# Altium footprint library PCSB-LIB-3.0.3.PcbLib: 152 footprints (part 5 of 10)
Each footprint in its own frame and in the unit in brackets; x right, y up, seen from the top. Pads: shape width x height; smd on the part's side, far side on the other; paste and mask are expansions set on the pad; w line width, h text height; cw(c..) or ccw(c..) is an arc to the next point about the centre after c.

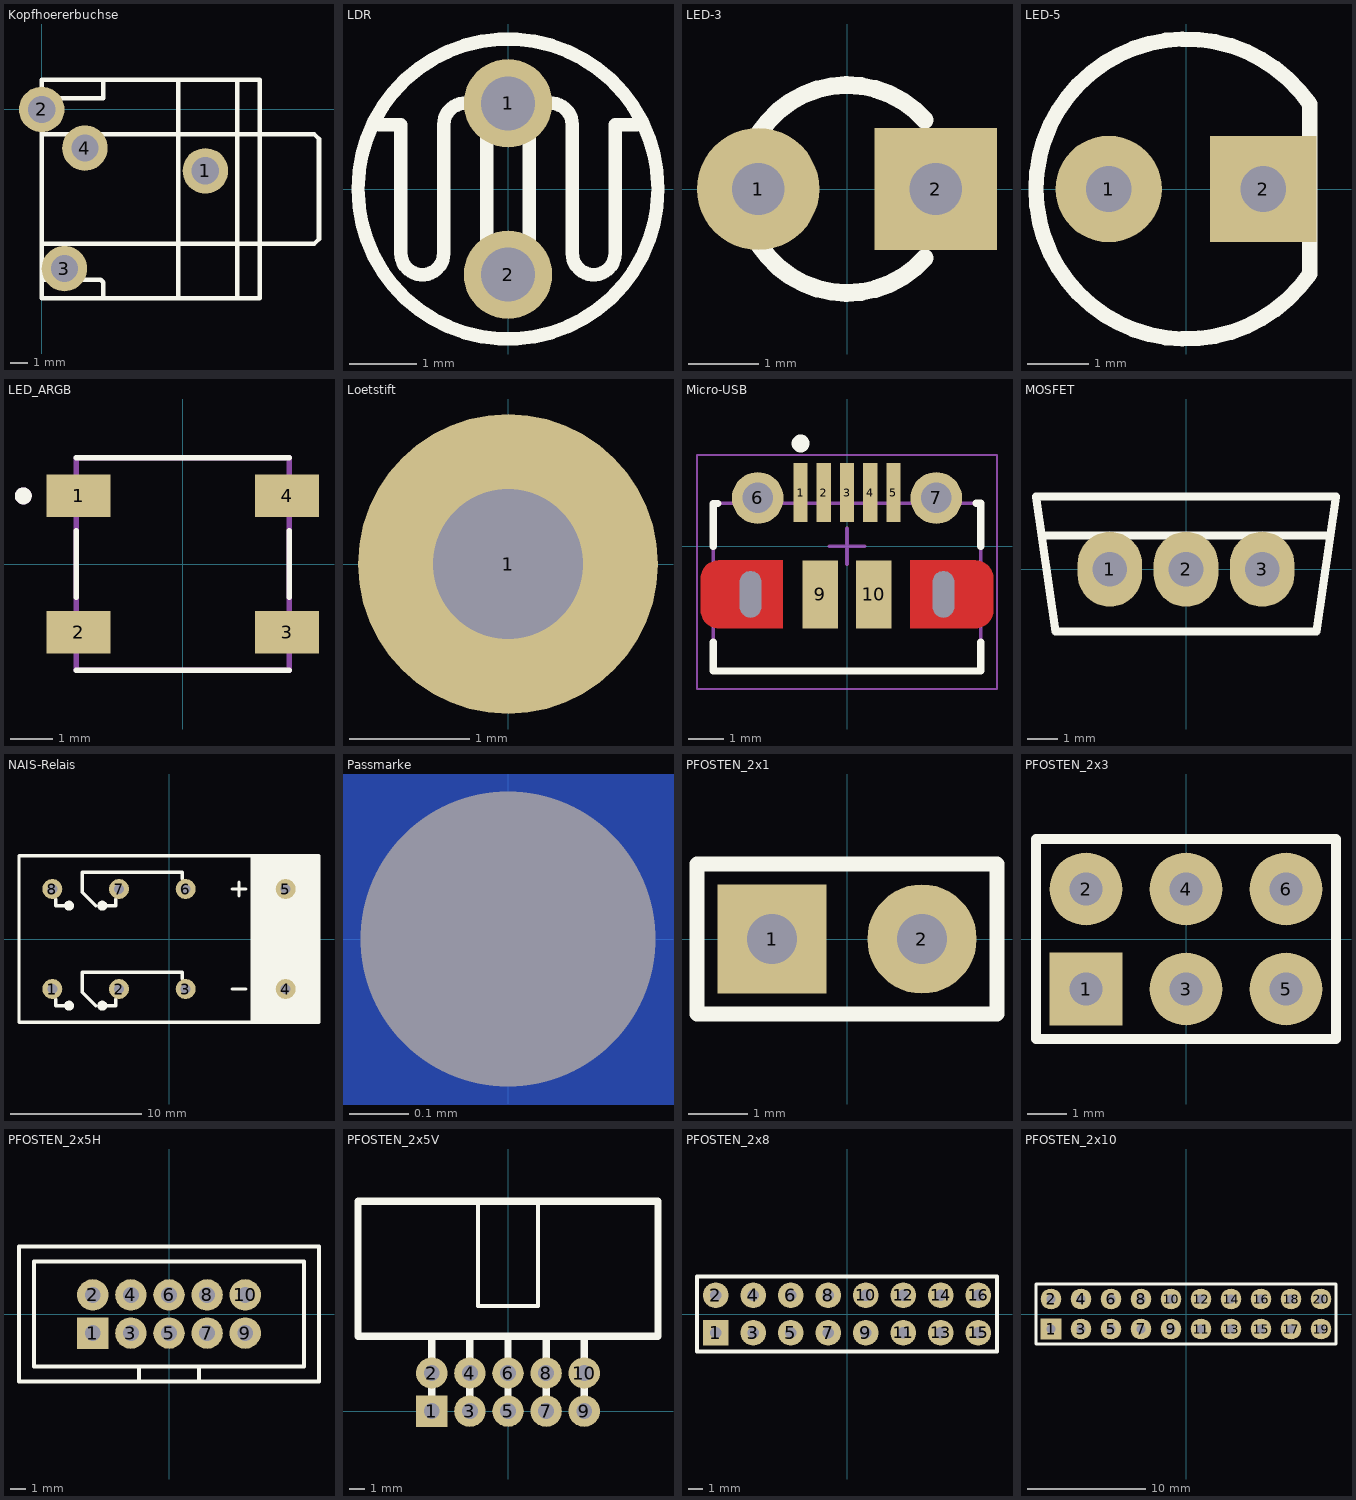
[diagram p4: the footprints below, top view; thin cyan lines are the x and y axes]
## Kopfhoererbuchse [mil]
pads (4):
  round 100 hole 60: 1(360,-135) 2(0,0) 3(50,-350) 4(95,-85)
Top Overlay:
  lines w10: 0,-375 130,-375 135,-380 135,-415 ; 0,-295 480,-295 600,-295 610,-285 610,-65 600,-55 480,-55 0,-55 ; 0,25 135,25 135,65 ; 300,-415 300,65 ; 430,-415 430,65 ; 0,-415 480,-415 480,65 0,65 0,-415

## LDR [mm]
pads (2):
  round 1.308 hole 0.8: 1(0,1.27) 2(0,-1.27)
Top Overlay:
  circle w0.2: c0,0 r2.222
  lines w0.2: -1.905,0.953 -1.587,0.953 -1.587,-0.953 ccw(c-1.27,-0.953) -0.953,-0.953 -0.953,0.953 cw(c-0.635,0.953) -0.318,0.953 -0.318,-0.953 ; 0.318,-0.953 0.318,0.953 cw(c0.635,0.953) 0.953,0.953 0.953,-0.953 ccw(c1.27,-0.953) 1.587,-0.953 1.587,0.953 1.905,0.953
Mechanical 13:
  lines w0.2: -0.318,-0.953 ccw(c0,-0.953) 0.318,-0.953

## LED-3 [mm]
pads (2):
  round 1.75 hole 0.75: 1(-1.27,0)
  rect 1.75x1.75 hole 0.75: 2(1.27,0)
Top Overlay:
  lines w0.254: 1.111,-0.988 cw(c0,0) 1.111,0.988 ; 1.397,-0.508 1.397,0.508

## LED-5 [mm]
pads (2):
  round 1.75 hole 0.75: 1(-1.27,0)
  rect 1.75x1.75 hole 0.75: 2(1.27,0)
Top Overlay:
  lines w0.254: 2.032,-1.397 cw(c0,0) 2.032,1.397 2.032,-1.397

## LED_ARGB [mm]
pads (4):
  rect 1.5x1 smd: 1(-2.45,1.6) 2(-2.45,-1.6) 3(2.45,-1.6) 4(2.45,1.6)
Top Overlay:
  circle w0.2: c-3.75,1.6 r0.1
  lines w0.127: -2.5,-2.5 2.5,-2.5 ; -2.5,-0.787 -2.5,0.787 ; -2.5,2.5 2.5,2.5 ; 2.5,-0.787 2.5,0.787
Mechanical 13:
  circle w0.2: c-3.75,1.6 r0.1
  lines w0.127: -2.5,-2.5 2.5,-2.5 2.5,2.5 -2.5,2.5 -2.5,-2.5

## Loetstift [mm]
pads (1):
  round 2.5 hole 1.25: 1(0,0)

## Micro-USB [mm] "USB, MICRO B, Body 7.491x4.695 mm, Pitch 0.65 mm"
height 2.673
pads (11):
  rect 0.4x1.65 smd: 1(-1.3,1.5) 2(-0.65,1.5) 3(0,1.5) 4(0.65,1.5) 5(1.3,1.5)
  round 1.45 hole 0.85: 6(-2.5,1.35) 7(2.5,1.35)
  rrect50% 0x0 hole 0.6 slot 1.3 at 90 deg: 8(-2.7,-1.35) 11(2.7,-1.35)
  rect 1x1.9 smd: 9(-0.75,-1.35) 10(0.75,-1.35)
Top Layer:
  circle w0.5: c3.6,-0.9 r0.25
  circle w0.5: c3.6,-1.8 r0.25
  circle w0.5: c-3.6,-0.9 r0.25
  circle w0.5: c-3.6,-1.8 r0.25
  region: 3.6,-0.9 3.6,-1.8 4.1,-1.8 4.1,-0.9
  region: 1.775,-0.4 1.775,-2.3 3.6,-2.3 3.6,-0.4
  region: -3.6,-1.8 -3.6,-0.9 -4.1,-0.9 -4.1,-1.8
  region: -1.8,-2.3 -1.8,-0.4 -3.6,-0.4 -3.6,-2.3
Top Overlay:
  circle w0.25: c-1.3,2.875 r0.125
  lines w0.2: -3.745,-2.688 -3.745,-3.5 3.745,-3.5 3.745,-2.688 ; -3.745,-0.012 -3.745,1.195 -3.614,1.195 ; 3.615,1.2 3.745,1.2 3.745,-0.012
Mechanical 13:
  lines w0.1: -3.75,1.2 3.745,1.2 3.745,-3.5 -3.745,-3.5 -3.745,1.195
Mechanical 15:
  lines w0.05: -4.2,-4 4.2,-4 4.2,2.55 -4.2,2.55 -4.2,-4
  lines w0.1: -0.5,0 0.5,0 ; 0,-0.5 0,0.5

## MOSFET [mm]
pads (3):
  oval 2.15x2.5 hole 1.15: 1(-2.54,0) 2(0,0) 3(2.54,0)
Top Overlay:
  lines w0.254: -4.812,1.125 4.808,1.125 ; -5,2.425 0,2.425 5,2.425 4.35,-2.075 0,-2.075 -4.35,-2.075 -5,2.425

## NAIS-Relais [mil]
pads (8):
  round 60 hole 30: 1(-350,-150) 2(-150,-150) 3(50,-150) 4(350,-150) 5(350,150) 6(50,150) 7(-150,150) 8(-350,150)
Top Overlay:
  circle w10: c-300,-200 r10
  circle w10: c-200,-200 r10
  circle w10: c-300,100 r10
  circle w10: c-200,100 r10
  rectangle: 250,-250 450,250
  region: -310,-190 -290,-190 -290,-210 -310,-210
  region: -210,-190 -190,-190 -190,-210 -210,-210
  region: -206,109 -192,109 -192,93 -194,91 -207,91 -207,108
  region: -306,109 -305,108 -293,108 -293,94 -295,92 -302,92 -302,103 -307,108
  region: -290,100 -300,100 -299,99 -299,90 -300,90 -302,92 -300,94 -300,102 -295,97 -295,92
  lines w10: -340,-180 -340,-200 -300,-200 ; -340,120 -340,100 -300,100 ; -220,-200 -260,-160 -260,-120 -260,-100 40,-100 40,-120 ; -220,100 -260,140 -260,180 -260,200 40,200 40,180 ; -200,-200 -160,-200 -160,-180 ; -200,100 -160,100 -160,120 ; 190,-150 230,-150 ; 190,150 230,150 ; 210,130 210,170 ; 250,-250 250,250 ; -450,-250 450,-250 450,250 -450,250 -450,-250

## Passmarke [mm]
pads (1):
  round 0 hole 0.5 unplated: 0(0,0)
Bottom Layer:
  circle w0.5: c0,0 r0.25

## PFOSTEN_2x1 [mm]
pads (2):
  rect 1.85x1.85 hole 0.85 mask+0.102: 1(-1.27,0)
  round 1.85 hole 0.85 mask+0.102: 2(1.27,0)
Top Overlay:
  lines w0.254: -2.54,-1.27 -2.54,1.27 2.54,1.27 2.54,-1.27 -2.54,-1.27

## PFOSTEN_2x3 [mm]
pads (6):
  rect 1.85x1.85 hole 0.85 mask+0.102: 1(-2.54,-1.27)
  round 1.85 hole 0.85 mask+0.102: 2(-2.54,1.27) 3(0,-1.27) 4(0,1.27) 5(2.54,-1.27) 6(2.54,1.27)
Top Overlay:
  lines w0.254: -3.81,-2.54 3.81,-2.54 3.81,2.54 -3.81,2.54 -3.81,-2.54

## PFOSTEN_2x5H [mm]
height 9
pads (10):
  rect 2.1x2.1 hole 1.05 mask+0.102: 1(-5.08,-1.27)
  round 2.1 hole 1.05 mask+0.102: 2(-5.08,1.27) 3(-2.54,-1.27) 4(-2.54,1.27) 5(0,-1.27) 6(0,1.27) 7(2.54,-1.27) 8(2.54,1.27) 9(5.08,-1.27) 10(5.08,1.27)
Top Overlay:
  lines w0.254: -2,-4.5 -2,-3.5 ; -0.5,4.5 10,4.5 10,-4.5 -10,-4.5 -10,4.5 0,4.5 ; 2,-4.5 2,-3.5 ; -9,-3.5 -9,3.5 9,3.5 9,-3.5 -9,-3.5

## PFOSTEN_2x5V [mm]
height 9
pads (10):
  rect 2.1x2.1 hole 1.05 mask+0.102: 1(-5.08,0)
  round 2.1 hole 1.05 mask+0.102: 2(-5.08,2.54) 3(-2.54,0) 4(-2.54,2.54) 5(0,0) 6(0,2.54) 7(2.54,0) 8(2.54,2.54) 9(5.08,0) 10(5.08,2.54)
Top Overlay:
  lines w0.254: -2,14 -2,7 2,7 2,14
  lines w0.5: -5.08,0 -5.08,5 ; -2.54,0 -2.54,5 ; 0,0 0,5 ; 2.54,0 2.54,5 ; 5.08,0 5.08,5 ; 0,5 10,5 10,14 -10,14 -10,5 0,5

## PFOSTEN_2x8 [mm]
pads (16):
  rect 1.75x1.75 hole 0.75: 1(-8.89,-1.27)
  round 1.75 hole 0.75: 2(-8.89,1.27) 3(-6.35,-1.27) 4(-6.35,1.27) 5(-3.81,-1.27) 6(-3.81,1.27) 7(-1.27,-1.27) 8(-1.27,1.27) 9(1.27,-1.27) 10(1.27,1.27) 11(3.81,-1.27) 12(3.81,1.27) 13(6.35,-1.27) 14(6.35,1.27) 15(8.89,-1.27) 16(8.89,1.27)
Top Overlay:
  lines w0.254: -10.16,-2.54 10.16,-2.54 10.16,2.54 -10.16,2.54 -10.16,-2.54

## PFOSTEN_2x10 [mm]
pads (20):
  rect 1.75x1.75 hole 0.75: 1(-11.43,-1.27)
  round 1.75 hole 0.75: 2(-11.43,1.27) 3(-8.89,-1.27) 4(-8.89,1.27) 5(-6.35,-1.27) 6(-6.35,1.27) 7(-3.81,-1.27) 8(-3.81,1.27) 9(-1.27,-1.27) 10(-1.27,1.27) 11(1.27,-1.27) 12(1.27,1.27) 13(3.81,-1.27) 14(3.81,1.27) 15(6.35,-1.27) 16(6.35,1.27) 17(8.89,-1.27) 18(8.89,1.27) 19(11.43,-1.27) 20(11.43,1.27)
Top Overlay:
  lines w0.254: -12.7,-2.54 12.7,-2.54 12.7,2.54 -12.7,2.54 -12.7,-2.54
